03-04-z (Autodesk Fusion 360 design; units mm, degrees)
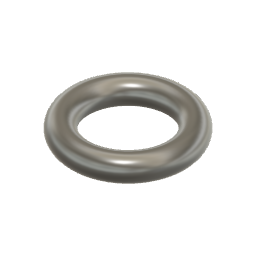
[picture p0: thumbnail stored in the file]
step "トーラス プリミティブ" MinorDiameter 20 MajorDiameter 80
